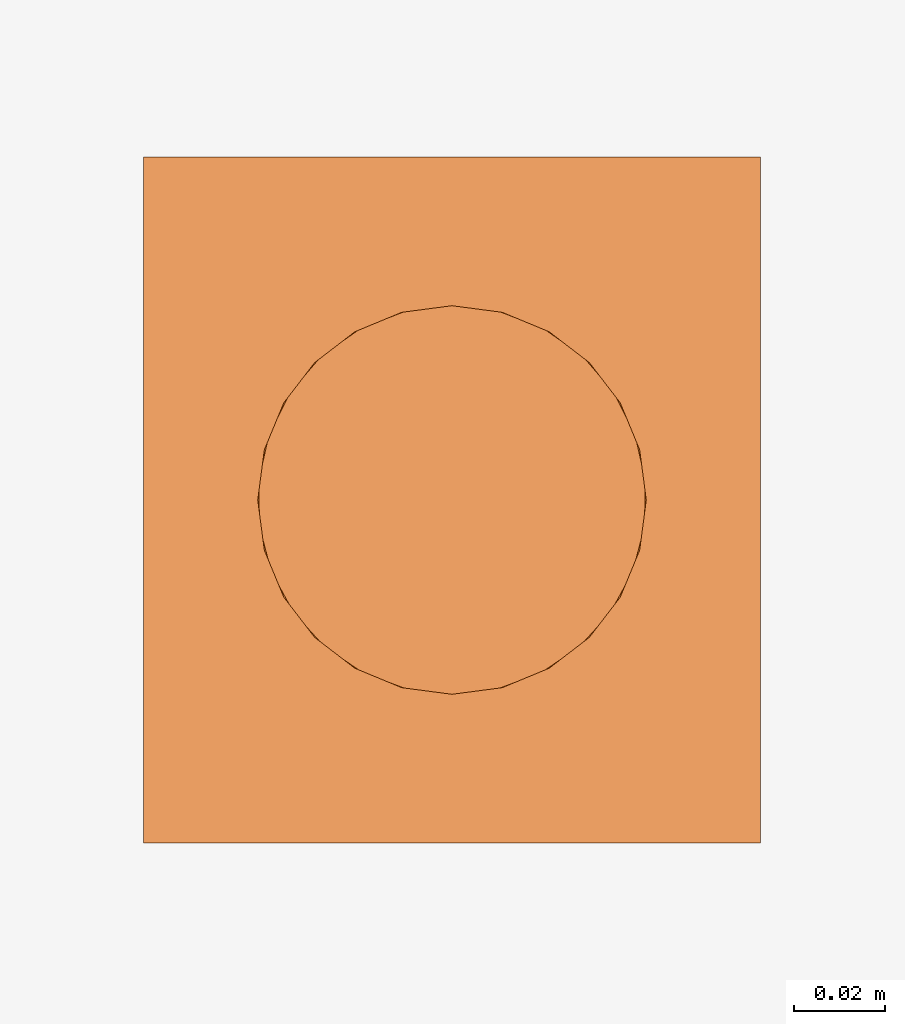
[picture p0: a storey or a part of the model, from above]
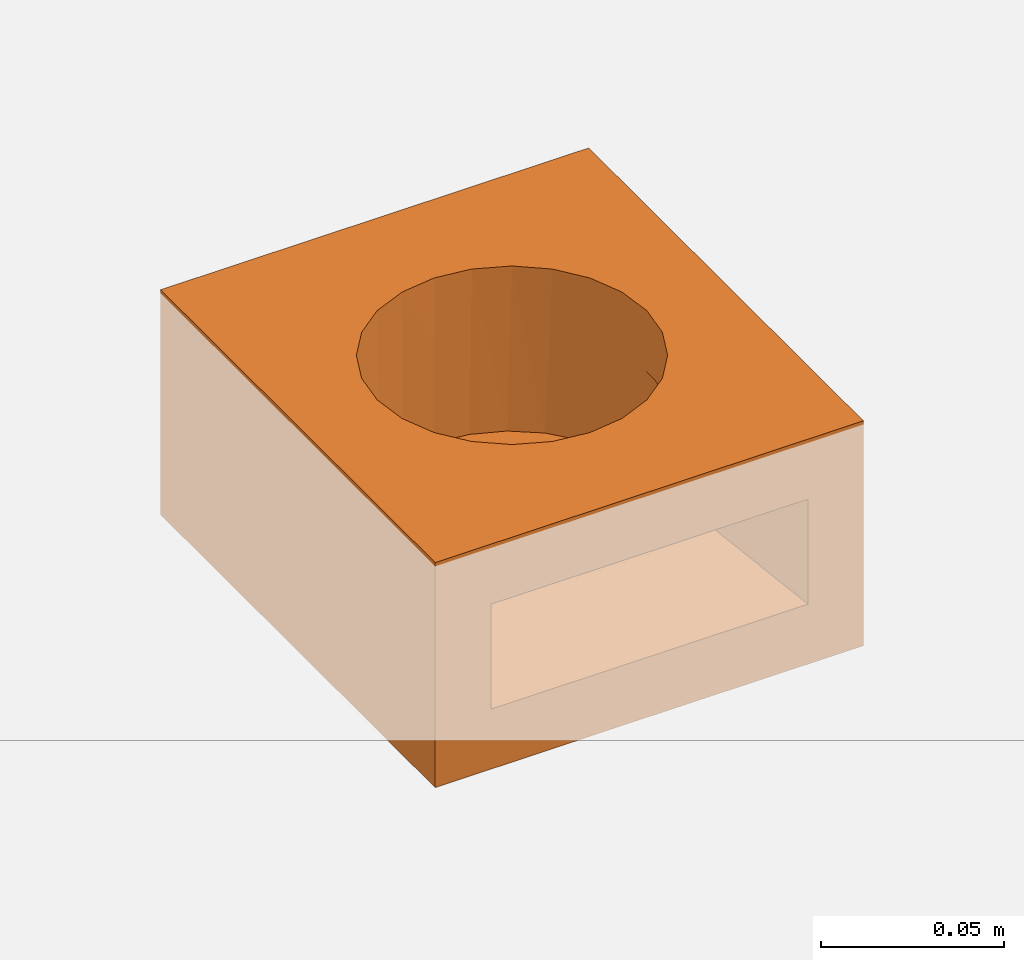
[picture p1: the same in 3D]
Properties of the parts of a building model (IFC2X3)

# File
Description: ViewDefinition [CoordinationView]
File name: 23450 - CFD075 Downpipe connector - 75mm high.ifc
Time: 2013-10-16T12:19:25
Written by: Autodesk Revit 2013
Made in: 20120221_2030(x64)

# IfcProject, Project Number
LongName: Project Name; Phase: Project Status

# IfcSite, Default
RefLatitude: 42, 21, 30, 344238; RefLongitude: -71, -3, -35, -194702; RefElevation: 0 mm

# IfcBuilding
Pset_BuildingCommon - NumberOfStoreys: 1
Other - Project Issue Date: Issue Date; Project Number: Project Number; Project Address: ## Street City, State Zip; Project Name: Project Name; Client Name: Owner; Project Status: Project Status

# IfcBuildingStorey, Level 1
LongName: Level 1; Elevation: 0 mm
Constraints - Elevation Base: 0; Elevation: 0 mm
Graphics - Symbol at End 2 Default: yes; Symbol: M_Level Head - Circle: M_Level Head - Circle; Symbol at End 1 Default: no; Line Pattern: Center; Line Weight: 1; Color: 0
Dimensions - Computation Height: 0 mm
Identity Data - Name: Level 1; Structural: no; Building Story: yes

# IfcBuildingElementProxy: 23450 - CFD075 Downpipe connector - 75mm high, Civil-Drainage-Channel-ACO-MultiDrain-M100D-Channel-System:23450 - CFD075 Downpipe connector - 75mm high:23450 - CFD075 Downpipe connector - 75mm high:1089344
In: Level 1
Material: Grey Polymer Concrete
Construction - 12673 - Grating - Intercept - Ductile Iron - 500mm Long: no; 12614 - Grating - Slotted - Galvanised Steel - 1000mm Long: no; 23408 - Grating - Slotted - Ductile Iron - 500mm Long: no; 23406 - Grating - Solid Cover - Ductile Iron - 500mm Long: no; 12657 - Grating - Perforated - Galvanised Steel - 500mm long: no; 12656 - Grating - Perforated - Galvanised Steel - 1000mm long: no; 12615 - Grating - Slotted - Galvanised Steel - 500mm Long: no; 12610 - Grating - Slotted - Galvanised Steel - 1000mm Long: no; 12666 - Grating - Perforated - Galvanised Steel - 1000mm Long: no; 12667 - Grating - Perforated - Galvanised Steel - 500mm Long: no; 12619 - Grating - Mesh - Galvanised Steel - 500mm Long: no; 23409 - Grating - ATec coated - Heelguard™ - Ductile Iron - 500mm Long: no; 12611 - Grating - Slotted - Galvanised Steel - 500mm Long: no; 23404 - Universal Endcap - Female End: no; 12680 - Grating - Heelguard™ - Composite Black - 500mm Long: no; 12618 - Grating - Mesh - Galvanised Steel - 1000mm Long: no; 23405 - Grating - Heelguard™ - Ductile Iron - 500mm Long: no; 23404 - Universal Endcap - Male End: no; Shallow Depth Channel with seal: no; Sloping Channel: no; Constant Depth Channel: no; Sump Unit: no; Shallow Depth Channel: no; 23452 - Kerb Outlet Half Batter: no; 23450 - Downpipe connector 75mm Depth: yes; 23453 - Kerb Outlet Bull Nose: no; 23451 - Downpipe connector 100mm Depth: no; Constant Depth Junction Channel: no; Grating 1000mm: no
Phasing - Phase Created: New Construction
Constraints - Level: Level: Level 1; Moves With Nearby Elements: no
Dimensions - Length: 150 mm; Volume: 1062604 mm3; FloorCut_Length: -150 mm; Custom_Value_Length: 850 mm; EndCap Position: 150 mm; EndCap_Female_Height: 249 mm; FloorCut_Width: 135 mm; ShallowOverallDepth: 75 mm; Endcap_Void_Depth: 6000 mm; Depth: 150 mm; SlopingInvertDepth: 125 mm; FloorCut_HorPosition: 67.5 mm; SlopingEndInvertDepth: 130 mm; FloorCut_Depth: 75 mm; SlopingOverallDepth: 195 mm; ShallowInvDepth: 55 mm; SlopingEndOverallDepth: 200 mm; Length Drain: -1000 mm; InvDepth: 80 mm; EndCap_Height: 249 mm
Pset_BuildingElementProxyCommon - Reference: 23450 - CFD075 Downpipe connector - 75mm high
Identity Data - Assembly Description: Rain Water Drainage; Assembly Code: D2040; Watermark 2: This file is watermarked and users are prohibited to reproduce, adapt, distribute this information; Watermark 1: This file is the property of ACO Technologies PLC; Model: ACO MultiDrain MD - M100D; Model Description: Channel drainage system; Product Page URL: http://www.aco.co.uk/product_detail.php?id=15; Product Code: 23450; URL: www.aco.co.uk; Fax: +44 (0)1462 815895; Price: POA - contact ACO; Address: ACO Business Park, Hitchin Road, Shefford, Bedfordshire, United Kingdom SG17 5TE; Maintenance guidelines: http://www.aco.co.uk/download.php?id=173; Installation guidelines: http://www.aco.co.uk/download.php?id=173; Cost: 0; OmniClass Title: Rainwater Removal; Product brochure: http://www.aco.co.uk/download.php?id=173; Telephone: +44 (0)1462 816666; Watermarked By: www.aco.co.uk; Type Comments: ACO MultiDrain M100D CFD075 Downpipe Connector Grey; e-mail Technical: technical@aco.co.uk; Manufacturer: ACO Technologies plc - ACO Water Management Division; OmniClass Number: 23.70.50.24; Watermarked With: BIM Manager Premium Suite; e-mail Sales: customersupport@aco.co.uk
Data - Load Class: N/A; ACO Hydraulic Design Software: N/A; Concrete Surround Volume - Load Class D 400 - Concrete Pavement: N/A; Hydraulic Performance: N/A; Invert Depth: N/A; Channel C.S.A: N/A; Product Standard: N/A; Product Weight: 2.4kg; Concrete Surround Volume - Load Class B 125 - C 250 - Concrete Pavement: N/A; Product Dimensions: 150mm x 135mm x 75mm (LxWxH); Concrete Surround Volume - Load Class A 15 - Concrete Pavement: N/A; Pre-formed Outlet Ø: N/A; Installation - Concrete Grade: N/A
General - SerialNumber: 0; TagNumber: 0
Model Properties - Grating Product code 12619: N/A; Grating Product code 12666: N/A; Grating Product code 23408: N/A; Grating Product code 23405: N/A; Grating Product code 12673: N/A; Grating Product code 12615: N/A; Grating Product code 12610: N/A; Grating Product code 23406: N/A; Grating Product code 12680: N/A; Grating Product code 12618: N/A; End Cap Product code 23404: N/A; Grating Product code 12656: N/A; Grating Product code 12667: N/A; Grating Product code 12657: N/A; Grating Product code 12611: N/A; Grating Product code 12614: N/A
Green Building Properties - Edge Rail Recyclable: N/A; Channel Recyclable: Fully recyclable; Edge Rail Recycled Material Content: N/A; Channel Recycled Material Content: 20% minimum
Materials and Finishes - Edge Rail Colour: N/A; Channel Material: Vienite® Synthetic Resin Concrete; Edge Rail Material: N/A; Edge Rail Finish: N/A; Channel Colour: Grey
Other - Revision: 1; CreatedBy: www.aco.co.uk

# IfcOpeningElement: Recess
In: Level 1
Constraints - Level: Level: Level 1; Height Offset From Level: 0 mm; Room Bounding: yes; Related to Mass: no
Dimensions - Area: 27030000 mm2; Perimeter: 20800 mm; Volume: 10810481250 mm3; Thickness: 400 mm
Structural - Enable Analytical Model: no; Structural: no
Phasing - Phase Created: New Construction
Construction - Default Thickness: 400 mm; Function: 0
Analytical Properties - Absorptance: 0.1; Roughness: 1
Graphics - Coarse Scale Fill Color: 0
Materials and Finishes - Structural Material: Plant

# IfcSlab: Floor:Generic Floor - 400mm, Floor:Generic Floor - 400mm:193825
In: Level 1
PredefinedType: FLOOR; Material: Plant 400 mm
Constraints - Level: Level: Level 1; Height Offset From Level: 0 mm; Room Bounding: yes; Related to Mass: no
Dimensions - Area: 27030000 mm2; Perimeter: 20800 mm; Volume: 10810481250 mm3; Thickness: 400 mm
Structural - Enable Analytical Model: no; Structural: no
Phasing - Phase Created: New Construction
Pset_SlabCommon - Reference: Generic Floor - 400mm; IsExternal: no; LoadBearing: yes
Construction - Default Thickness: 400 mm; Function: 0
Analytical Properties - Absorptance: 0.1; Roughness: 1
Graphics - Coarse Scale Fill Color: 0
Materials and Finishes - Structural Material: Plant
